VERSION 5.8 ;
BUSBITCHARS "[]" ;
DIVIDERCHAR "/" ;
UNITS
    DATABASE MICRONS 2000 ;
END UNITS

VIA int8_mac_pp_feedback_via1_2_960_340_1_3_300_300
  VIARULE Via1Array-0 ;
  CUTSIZE 0.07 0.07 ;
  LAYERS metal1 via1 metal2 ;
  CUTSPACING 0.08 0.08 ;
  ENCLOSURE 0.035 0.05 0.035 0.035 ;
  ROWCOL 1 3 ;
END int8_mac_pp_feedback_via1_2_960_340_1_3_300_300

VIA int8_mac_pp_feedback_via2_3_960_340_1_3_320_320
  VIARULE Via2Array-0 ;
  CUTSIZE 0.07 0.07 ;
  LAYERS metal2 via2 metal3 ;
  CUTSPACING 0.09 0.09 ;
  ENCLOSURE 0.035 0.035 0.035 0.035 ;
  ROWCOL 1 3 ;
END int8_mac_pp_feedback_via2_3_960_340_1_3_320_320

VIA int8_mac_pp_feedback_via3_4_960_340_1_3_320_320
  VIARULE Via3Array-0 ;
  CUTSIZE 0.07 0.07 ;
  LAYERS metal3 via3 metal4 ;
  CUTSPACING 0.09 0.09 ;
  ENCLOSURE 0.035 0.035 0.045 0.035 ;
  ROWCOL 1 3 ;
END int8_mac_pp_feedback_via3_4_960_340_1_3_320_320

VIA int8_mac_pp_feedback_via4_5_960_2800_5_2_600_600
  VIARULE Via4Array-0 ;
  CUTSIZE 0.14 0.14 ;
  LAYERS metal4 via4 metal5 ;
  CUTSPACING 0.16 0.16 ;
  ENCLOSURE 0.02 0 0 0 ;
  ROWCOL 5 2 ;
END int8_mac_pp_feedback_via4_5_960_2800_5_2_600_600

VIA int8_mac_pp_feedback_via5_6_960_2800_5_2_600_600
  VIARULE Via5Array-0 ;
  CUTSIZE 0.14 0.14 ;
  LAYERS metal5 via5 metal6 ;
  CUTSPACING 0.16 0.16 ;
  ENCLOSURE 0 0 0 0 ;
  ROWCOL 5 2 ;
END int8_mac_pp_feedback_via5_6_960_2800_5_2_600_600

VIA int8_mac_pp_feedback_via6_7_960_2800_4_1_600_600
  VIARULE Via6Array-0 ;
  CUTSIZE 0.14 0.14 ;
  LAYERS metal6 via6 metal7 ;
  CUTSPACING 0.16 0.16 ;
  ENCLOSURE 0 0 0.13 0.18 ;
  ROWCOL 4 1 ;
END int8_mac_pp_feedback_via6_7_960_2800_4_1_600_600

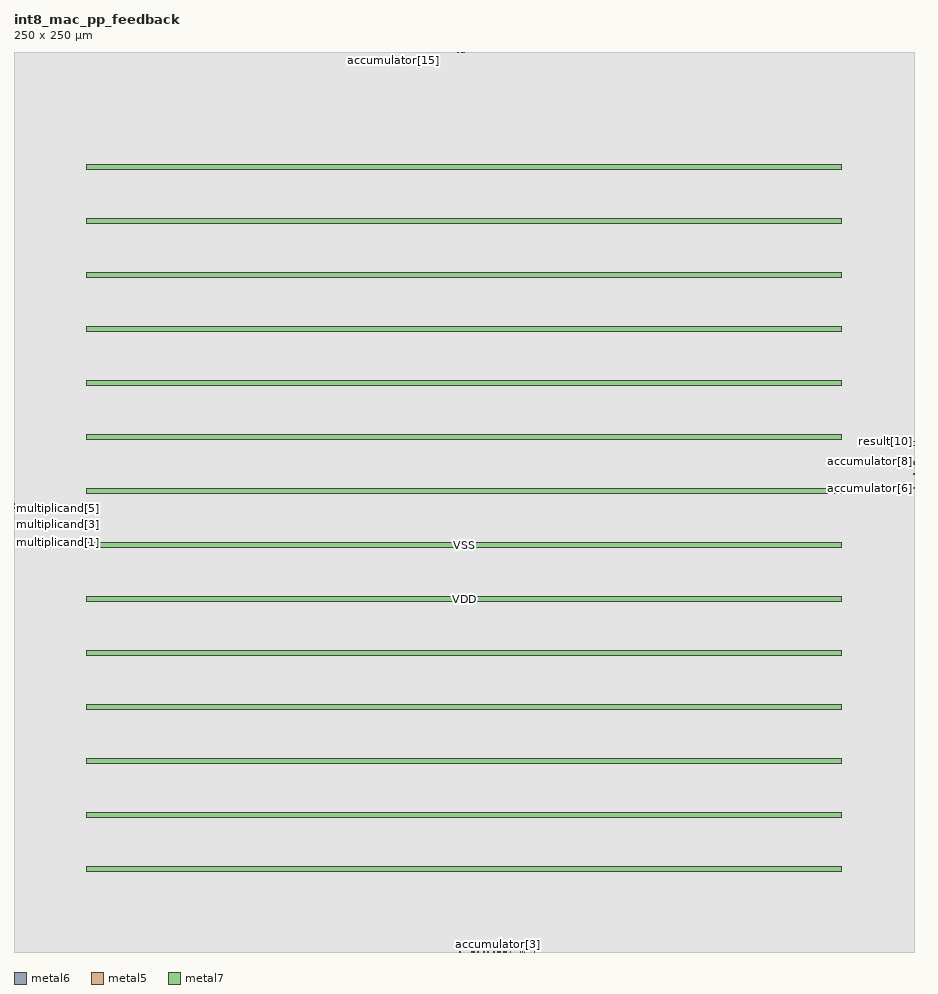
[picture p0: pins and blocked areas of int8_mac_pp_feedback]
MACRO int8_mac_pp_feedback
  FOREIGN int8_mac_pp_feedback 0 0 ;
  CLASS BLOCK ;
  SIZE 250 BY 250 ;
  PIN accumulator[0]
    DIRECTION INPUT ;
    USE SIGNAL ;
    PORT
      LAYER metal6 ;
        RECT  127.705 0 127.845 0.14 ;
    END
  END accumulator[0]
  PIN accumulator[10]
    DIRECTION INPUT ;
    USE SIGNAL ;
    PORT
      LAYER metal6 ;
        RECT  118.745 249.86 118.885 250 ;
    END
  END accumulator[10]
  PIN accumulator[11]
    DIRECTION INPUT ;
    USE SIGNAL ;
    PORT
      LAYER metal6 ;
        RECT  115.385 249.86 115.525 250 ;
    END
  END accumulator[11]
  PIN accumulator[12]
    DIRECTION INPUT ;
    USE SIGNAL ;
    PORT
      LAYER metal6 ;
        RECT  111.465 249.86 111.605 250 ;
    END
  END accumulator[12]
  PIN accumulator[13]
    DIRECTION INPUT ;
    USE SIGNAL ;
    PORT
      LAYER metal6 ;
        RECT  109.225 249.86 109.365 250 ;
    END
  END accumulator[13]
  PIN accumulator[14]
    DIRECTION INPUT ;
    USE SIGNAL ;
    PORT
      LAYER metal6 ;
        RECT  108.105 249.86 108.245 250 ;
    END
  END accumulator[14]
  PIN accumulator[15]
    DIRECTION INPUT ;
    USE SIGNAL ;
    PORT
      LAYER metal6 ;
        RECT  105.305 249.86 105.445 250 ;
    END
  END accumulator[15]
  PIN accumulator[1]
    DIRECTION INPUT ;
    USE SIGNAL ;
    PORT
      LAYER metal6 ;
        RECT  130.505 0 130.645 0.14 ;
    END
  END accumulator[1]
  PIN accumulator[2]
    DIRECTION INPUT ;
    USE SIGNAL ;
    PORT
      LAYER metal6 ;
        RECT  136.665 0 136.805 0.14 ;
    END
  END accumulator[2]
  PIN accumulator[3]
    DIRECTION INPUT ;
    USE SIGNAL ;
    PORT
      LAYER metal6 ;
        RECT  134.425 0 134.565 0.14 ;
    END
  END accumulator[3]
  PIN accumulator[4]
    DIRECTION INPUT ;
    USE SIGNAL ;
    PORT
      LAYER metal6 ;
        RECT  133.305 0 133.445 0.14 ;
    END
  END accumulator[4]
  PIN accumulator[5]
    DIRECTION INPUT ;
    USE SIGNAL ;
    PORT
      LAYER metal6 ;
        RECT  134.985 0 135.125 0.14 ;
    END
  END accumulator[5]
  PIN accumulator[6]
    DIRECTION INPUT ;
    USE SIGNAL ;
    PORT
      LAYER metal5 ;
        RECT  249.86 128.8 250 128.94 ;
    END
  END accumulator[6]
  PIN accumulator[7]
    DIRECTION INPUT ;
    USE SIGNAL ;
    PORT
      LAYER metal5 ;
        RECT  249.86 132.72 250 132.86 ;
    END
  END accumulator[7]
  PIN accumulator[8]
    DIRECTION INPUT ;
    USE SIGNAL ;
    PORT
      LAYER metal5 ;
        RECT  249.86 136.08 250 136.22 ;
    END
  END accumulator[8]
  PIN accumulator[9]
    DIRECTION INPUT ;
    USE SIGNAL ;
    PORT
      LAYER metal6 ;
        RECT  124.345 249.86 124.485 250 ;
    END
  END accumulator[9]
  PIN multiplicand[0]
    DIRECTION INPUT ;
    USE SIGNAL ;
    PORT
      LAYER metal5 ;
        RECT  0 112.56 0.14 112.7 ;
    END
  END multiplicand[0]
  PIN multiplicand[1]
    DIRECTION INPUT ;
    USE SIGNAL ;
    PORT
      LAYER metal5 ;
        RECT  0 113.68 0.14 113.82 ;
    END
  END multiplicand[1]
  PIN multiplicand[2]
    DIRECTION INPUT ;
    USE SIGNAL ;
    PORT
      LAYER metal5 ;
        RECT  0 114.24 0.14 114.38 ;
    END
  END multiplicand[2]
  PIN multiplicand[3]
    DIRECTION INPUT ;
    USE SIGNAL ;
    PORT
      LAYER metal5 ;
        RECT  0 116.48 0.14 116.62 ;
    END
  END multiplicand[3]
  PIN multiplicand[4]
    DIRECTION INPUT ;
    USE SIGNAL ;
    PORT
      LAYER metal5 ;
        RECT  0 117.04 0.14 117.18 ;
    END
  END multiplicand[4]
  PIN multiplicand[5]
    DIRECTION INPUT ;
    USE SIGNAL ;
    PORT
      LAYER metal5 ;
        RECT  0 123.2 0.14 123.34 ;
    END
  END multiplicand[5]
  PIN multiplicand[6]
    DIRECTION INPUT ;
    USE SIGNAL ;
    PORT
      LAYER metal5 ;
        RECT  0 124.32 0.14 124.46 ;
    END
  END multiplicand[6]
  PIN multiplicand[7]
    DIRECTION INPUT ;
    USE SIGNAL ;
    PORT
      LAYER metal6 ;
        RECT  124.905 249.86 125.045 250 ;
    END
  END multiplicand[7]
  PIN multiplier[0]
    DIRECTION INPUT ;
    USE SIGNAL ;
    PORT
      LAYER metal6 ;
        RECT  128.825 0 128.965 0.14 ;
    END
  END multiplier[0]
  PIN multiplier[1]
    DIRECTION INPUT ;
    USE SIGNAL ;
    PORT
      LAYER metal6 ;
        RECT  123.785 0 123.925 0.14 ;
    END
  END multiplier[1]
  PIN multiplier[2]
    DIRECTION INPUT ;
    USE SIGNAL ;
    PORT
      LAYER metal5 ;
        RECT  0 112 0.14 112.14 ;
    END
  END multiplier[2]
  PIN multiplier[3]
    DIRECTION INPUT ;
    USE SIGNAL ;
    PORT
      LAYER metal5 ;
        RECT  0 117.6 0.14 117.74 ;
    END
  END multiplier[3]
  PIN multiplier[4]
    DIRECTION INPUT ;
    USE SIGNAL ;
    PORT
      LAYER metal5 ;
        RECT  0 119.28 0.14 119.42 ;
    END
  END multiplier[4]
  PIN multiplier[5]
    DIRECTION INPUT ;
    USE SIGNAL ;
    PORT
      LAYER metal6 ;
        RECT  107.545 249.86 107.685 250 ;
    END
  END multiplier[5]
  PIN multiplier[6]
    DIRECTION INPUT ;
    USE SIGNAL ;
    PORT
      LAYER metal6 ;
        RECT  106.985 249.86 107.125 250 ;
    END
  END multiplier[6]
  PIN multiplier[7]
    DIRECTION INPUT ;
    USE SIGNAL ;
    PORT
      LAYER metal6 ;
        RECT  113.705 249.86 113.845 250 ;
    END
  END multiplier[7]
  PIN result[0]
    DIRECTION OUTPUT ;
    USE SIGNAL ;
    PORT
      LAYER metal6 ;
        RECT  127.145 0 127.285 0.14 ;
    END
  END result[0]
  PIN result[10]
    DIRECTION OUTPUT ;
    USE SIGNAL ;
    PORT
      LAYER metal5 ;
        RECT  249.86 141.68 250 141.82 ;
    END
  END result[10]
  PIN result[11]
    DIRECTION OUTPUT ;
    USE SIGNAL ;
    PORT
      LAYER metal6 ;
        RECT  123.225 249.86 123.365 250 ;
    END
  END result[11]
  PIN result[12]
    DIRECTION OUTPUT ;
    USE SIGNAL ;
    PORT
      LAYER metal6 ;
        RECT  115.945 249.86 116.085 250 ;
    END
  END result[12]
  PIN result[13]
    DIRECTION OUTPUT ;
    USE SIGNAL ;
    PORT
      LAYER metal6 ;
        RECT  112.025 249.86 112.165 250 ;
    END
  END result[13]
  PIN result[14]
    DIRECTION OUTPUT ;
    USE SIGNAL ;
    PORT
      LAYER metal6 ;
        RECT  108.665 249.86 108.805 250 ;
    END
  END result[14]
  PIN result[15]
    DIRECTION OUTPUT ;
    USE SIGNAL ;
    PORT
      LAYER metal6 ;
        RECT  105.865 249.86 106.005 250 ;
    END
  END result[15]
  PIN result[1]
    DIRECTION OUTPUT ;
    USE SIGNAL ;
    PORT
      LAYER metal6 ;
        RECT  131.625 0 131.765 0.14 ;
    END
  END result[1]
  PIN result[2]
    DIRECTION OUTPUT ;
    USE SIGNAL ;
    PORT
      LAYER metal6 ;
        RECT  137.785 0 137.925 0.14 ;
    END
  END result[2]
  PIN result[3]
    DIRECTION OUTPUT ;
    USE SIGNAL ;
    PORT
      LAYER metal6 ;
        RECT  136.105 0 136.245 0.14 ;
    END
  END result[3]
  PIN result[4]
    DIRECTION OUTPUT ;
    USE SIGNAL ;
    PORT
      LAYER metal6 ;
        RECT  141.145 0 141.285 0.14 ;
    END
  END result[4]
  PIN result[5]
    DIRECTION OUTPUT ;
    USE SIGNAL ;
    PORT
      LAYER metal6 ;
        RECT  141.705 0 141.845 0.14 ;
    END
  END result[5]
  PIN result[6]
    DIRECTION OUTPUT ;
    USE SIGNAL ;
    PORT
      LAYER metal6 ;
        RECT  144.505 0 144.645 0.14 ;
    END
  END result[6]
  PIN result[7]
    DIRECTION OUTPUT ;
    USE SIGNAL ;
    PORT
      LAYER metal6 ;
        RECT  140.585 0 140.725 0.14 ;
    END
  END result[7]
  PIN result[8]
    DIRECTION OUTPUT ;
    USE SIGNAL ;
    PORT
      LAYER metal5 ;
        RECT  249.86 135.52 250 135.66 ;
    END
  END result[8]
  PIN result[9]
    DIRECTION OUTPUT ;
    USE SIGNAL ;
    PORT
      LAYER metal5 ;
        RECT  249.86 140.56 250 140.7 ;
    END
  END result[9]
  PIN VSS
    DIRECTION INOUT ;
    USE GROUND ;
    PORT
      LAYER metal7 ;
        RECT  20.14 202.3 229.9 203.7 ;
        RECT  20.14 172.3 229.9 173.7 ;
        RECT  20.14 142.3 229.9 143.7 ;
        RECT  20.14 112.3 229.9 113.7 ;
        RECT  20.14 82.3 229.9 83.7 ;
        RECT  20.14 52.3 229.9 53.7 ;
        RECT  20.14 22.3 229.9 23.7 ;
    END
  END VSS
  PIN VDD
    DIRECTION INOUT ;
    USE POWER ;
    PORT
      LAYER metal7 ;
        RECT  20.14 217.3 229.9 218.7 ;
        RECT  20.14 187.3 229.9 188.7 ;
        RECT  20.14 157.3 229.9 158.7 ;
        RECT  20.14 127.3 229.9 128.7 ;
        RECT  20.14 97.3 229.9 98.7 ;
        RECT  20.14 67.3 229.9 68.7 ;
        RECT  20.14 37.3 229.9 38.7 ;
    END
  END VDD
  OBS
    LAYER metal1 ;
     RECT  0 0 250 250 ;
    LAYER metal2 ;
     RECT  0 0 250 250 ;
    LAYER metal3 ;
     RECT  0 0 250 250 ;
    LAYER metal4 ;
     RECT  0 0 250 250 ;
    LAYER metal5 ;
     RECT  0 0 250 250 ;
    LAYER metal6 ;
     RECT  0 0 250 250 ;
    LAYER metal7 ;
     RECT  0 0 250 250 ;
  END
END int8_mac_pp_feedback
END LIBRARY
